One B-rep face of a CAD part: STEP entity #879.
In plain terms, the planar face has unit normal (1, 0, 0).
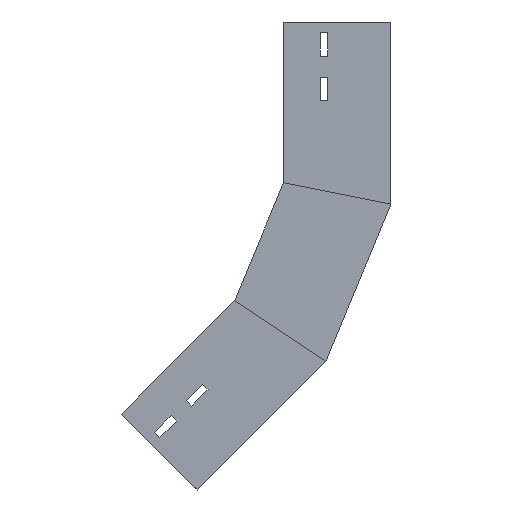
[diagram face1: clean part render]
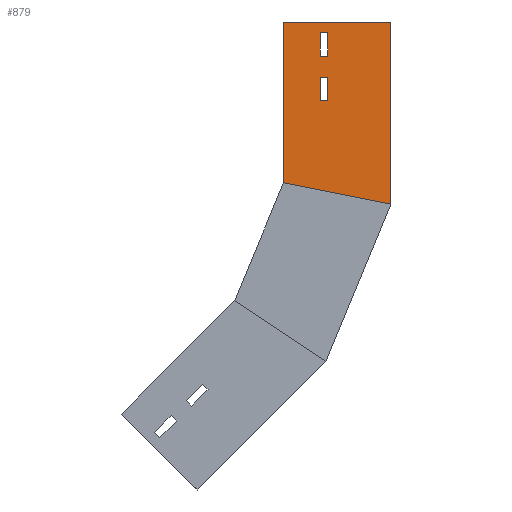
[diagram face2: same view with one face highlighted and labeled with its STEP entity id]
Its self-contained STEP definition (entity closure, numbers rounded to 3 decimals):
#16 = VECTOR ( 'NONE', #865, 1000. ) ;
#39 = VERTEX_POINT ( 'NONE', #1335 ) ;
#48 = CARTESIAN_POINT ( 'NONE',  ( 0., 170.324, -342.265 ) ) ;
#51 = EDGE_LOOP ( 'NONE', ( #257, #1183, #270, #1476 ) ) ;
#69 = FACE_BOUND ( 'NONE', #353, .T. ) ;
#74 = EDGE_CURVE ( 'NONE', #804, #1474, #315, .T. ) ;
#107 = EDGE_CURVE ( 'NONE', #872, #804, #1001, .T. ) ;
#166 = DIRECTION ( 'NONE',  ( 0., 0., 1. ) ) ;
#167 = CARTESIAN_POINT ( 'NONE',  ( 0., 86.366, -298.856 ) ) ;
#173 = CARTESIAN_POINT ( 'NONE',  ( 0., 204.739, -366.78 ) ) ;
#176 = VECTOR ( 'NONE', #993, 1000. ) ;
#191 = CARTESIAN_POINT ( 'NONE',  ( 0., 220.295, -382.337 ) ) ;
#195 = CARTESIAN_POINT ( 'NONE',  ( 0., 220.295, -382.337 ) ) ;
#232 = CARTESIAN_POINT ( 'NONE',  ( 0., 185.88, -357.821 ) ) ;
#242 = ORIENTED_EDGE ( 'NONE', *, *, #767, .F. ) ;
#257 = ORIENTED_EDGE ( 'NONE', *, *, #1152, .F. ) ;
#264 = VERTEX_POINT ( 'NONE', #232 ) ;
#270 = ORIENTED_EDGE ( 'NONE', *, *, #882, .F. ) ;
#273 = ORIENTED_EDGE ( 'NONE', *, *, #1032, .F. ) ;
#284 = DIRECTION ( 'NONE',  ( 0., -0.707, 0.707 ) ) ;
#315 = LINE ( 'NONE', #1125, #176 ) ;
#323 = VERTEX_POINT ( 'NONE', #48 ) ;
#353 = EDGE_LOOP ( 'NONE', ( #471, #1238, #273, #822 ) ) ;
#380 = CARTESIAN_POINT ( 'NONE',  ( 0., 175.274, -337.315 ) ) ;
#405 = LINE ( 'NONE', #167, #1059 ) ;
#412 = EDGE_CURVE ( 'NONE', #39, #872, #826, .T. ) ;
#419 = PLANE ( 'NONE',  #975 ) ;
#421 = CARTESIAN_POINT ( 'NONE',  ( 0., 60.655, -316.035 ) ) ;
#433 = CARTESIAN_POINT ( 'NONE',  ( 0., 60.655, -316.035 ) ) ;
#471 = ORIENTED_EDGE ( 'NONE', *, *, #107, .F. ) ;
#482 = CARTESIAN_POINT ( 'NONE',  ( 0., 215.346, -387.287 ) ) ;
#509 = LINE ( 'NONE', #753, #1492 ) ;
#515 = EDGE_CURVE ( 'NONE', #1289, #854, #991, .T. ) ;
#517 = LINE ( 'NONE', #982, #1249 ) ;
#559 = VERTEX_POINT ( 'NONE', #564 ) ;
#564 = CARTESIAN_POINT ( 'NONE',  ( 0., 251.291, -365.25 ) ) ;
#570 = VERTEX_POINT ( 'NONE', #1367 ) ;
#583 = CARTESIAN_POINT ( 'NONE',  ( 0., 131.366, -245.324 ) ) ;
#594 = CARTESIAN_POINT ( 'NONE',  ( 0., 175.274, -337.315 ) ) ;
#610 = CARTESIAN_POINT ( 'NONE',  ( 0., 145.431, -259.389 ) ) ;
#647 = DIRECTION ( 'NONE',  ( 0., -0.707, 0.707 ) ) ;
#649 = FACE_BOUND ( 'NONE', #51, .T. ) ;
#673 = VECTOR ( 'NONE', #284, 1000. ) ;
#698 = VECTOR ( 'NONE', #1081, 1000. ) ;
#705 = VERTEX_POINT ( 'NONE', #380 ) ;
#719 = EDGE_LOOP ( 'NONE', ( #1129, #1406, #724, #242 ) ) ;
#724 = ORIENTED_EDGE ( 'NONE', *, *, #1214, .T. ) ;
#728 = CARTESIAN_POINT ( 'NONE',  ( 0., 60.655, -316.035 ) ) ;
#753 = CARTESIAN_POINT ( 'NONE',  ( 0., 190.83, -352.872 ) ) ;
#754 = DIRECTION ( 'NONE',  ( 0., 0.707, 0.707 ) ) ;
#760 = DIRECTION ( 'NONE',  ( 0., 0.707, 0.707 ) ) ;
#766 = LINE ( 'NONE', #1440, #16 ) ;
#767 = EDGE_CURVE ( 'NONE', #927, #559, #1192, .T. ) ;
#804 = VERTEX_POINT ( 'NONE', #173 ) ;
#822 = ORIENTED_EDGE ( 'NONE', *, *, #74, .F. ) ;
#826 = LINE ( 'NONE', #1285, #1392 ) ;
#854 = VERTEX_POINT ( 'NONE', #1005 ) ;
#865 = DIRECTION ( 'NONE',  ( 0., 0.707, -0.707 ) ) ;
#872 = VERTEX_POINT ( 'NONE', #191 ) ;
#874 = CARTESIAN_POINT ( 'NONE',  ( 0., 190.83, -352.872 ) ) ;
#879 = ADVANCED_FACE ( 'NONE', ( #69, #649, #1455 ), #419, .F. ) ;
#881 = DIRECTION ( 'NONE',  ( -1., 0., 0. ) ) ;
#882 = EDGE_CURVE ( 'NONE', #323, #264, #766, .T. ) ;
#884 = DIRECTION ( 'NONE',  ( 0., 0.707, -0.707 ) ) ;
#927 = VERTEX_POINT ( 'NONE', #610 ) ;
#950 = EDGE_CURVE ( 'NONE', #705, #323, #1295, .T. ) ;
#975 = AXIS2_PLACEMENT_3D ( 'NONE', #433, #881, #166 ) ;
#982 = CARTESIAN_POINT ( 'NONE',  ( 0., 180.581, -435.96 ) ) ;
#991 = LINE ( 'NONE', #421, #1247 ) ;
#993 = DIRECTION ( 'NONE',  ( 0., -0.707, -0.707 ) ) ;
#1001 = LINE ( 'NONE', #195, #1120 ) ;
#1005 = CARTESIAN_POINT ( 'NONE',  ( 0., 180.581, -435.96 ) ) ;
#1031 = VECTOR ( 'NONE', #1082, 1000. ) ;
#1032 = EDGE_CURVE ( 'NONE', #1474, #39, #1067, .T. ) ;
#1059 = VECTOR ( 'NONE', #1225, 1000. ) ;
#1067 = LINE ( 'NONE', #482, #1031 ) ;
#1073 = DIRECTION ( 'NONE',  ( 0., -0.707, -0.707 ) ) ;
#1081 = DIRECTION ( 'NONE',  ( 0., 0.707, -0.707 ) ) ;
#1082 = DIRECTION ( 'NONE',  ( 0., 0.707, -0.707 ) ) ;
#1111 = CARTESIAN_POINT ( 'NONE',  ( 0., 199.789, -371.73 ) ) ;
#1120 = VECTOR ( 'NONE', #647, 1000. ) ;
#1125 = CARTESIAN_POINT ( 'NONE',  ( 0., 204.739, -366.78 ) ) ;
#1129 = ORIENTED_EDGE ( 'NONE', *, *, #1210, .T. ) ;
#1144 = EDGE_CURVE ( 'NONE', #264, #570, #509, .T. ) ;
#1152 = EDGE_CURVE ( 'NONE', #570, #705, #1441, .T. ) ;
#1183 = ORIENTED_EDGE ( 'NONE', *, *, #1144, .F. ) ;
#1192 = LINE ( 'NONE', #583, #698 ) ;
#1210 = EDGE_CURVE ( 'NONE', #927, #1289, #405, .T. ) ;
#1214 = EDGE_CURVE ( 'NONE', #854, #559, #517, .T. ) ;
#1225 = DIRECTION ( 'NONE',  ( 0., -0.831, -0.556 ) ) ;
#1238 = ORIENTED_EDGE ( 'NONE', *, *, #412, .F. ) ;
#1243 = VECTOR ( 'NONE', #1073, 1000. ) ;
#1247 = VECTOR ( 'NONE', #884, 1000. ) ;
#1249 = VECTOR ( 'NONE', #760, 1000. ) ;
#1285 = CARTESIAN_POINT ( 'NONE',  ( 0., 220.295, -382.337 ) ) ;
#1289 = VERTEX_POINT ( 'NONE', #728 ) ;
#1295 = LINE ( 'NONE', #594, #1243 ) ;
#1332 = DIRECTION ( 'NONE',  ( 0., 0.707, 0.707 ) ) ;
#1335 = CARTESIAN_POINT ( 'NONE',  ( 0., 215.346, -387.287 ) ) ;
#1367 = CARTESIAN_POINT ( 'NONE',  ( 0., 190.83, -352.872 ) ) ;
#1392 = VECTOR ( 'NONE', #754, 1000. ) ;
#1406 = ORIENTED_EDGE ( 'NONE', *, *, #515, .T. ) ;
#1440 = CARTESIAN_POINT ( 'NONE',  ( 0., 185.88, -357.821 ) ) ;
#1441 = LINE ( 'NONE', #874, #673 ) ;
#1455 = FACE_OUTER_BOUND ( 'NONE', #719, .T. ) ;
#1474 = VERTEX_POINT ( 'NONE', #1111 ) ;
#1476 = ORIENTED_EDGE ( 'NONE', *, *, #950, .F. ) ;
#1492 = VECTOR ( 'NONE', #1332, 1000. ) ;
